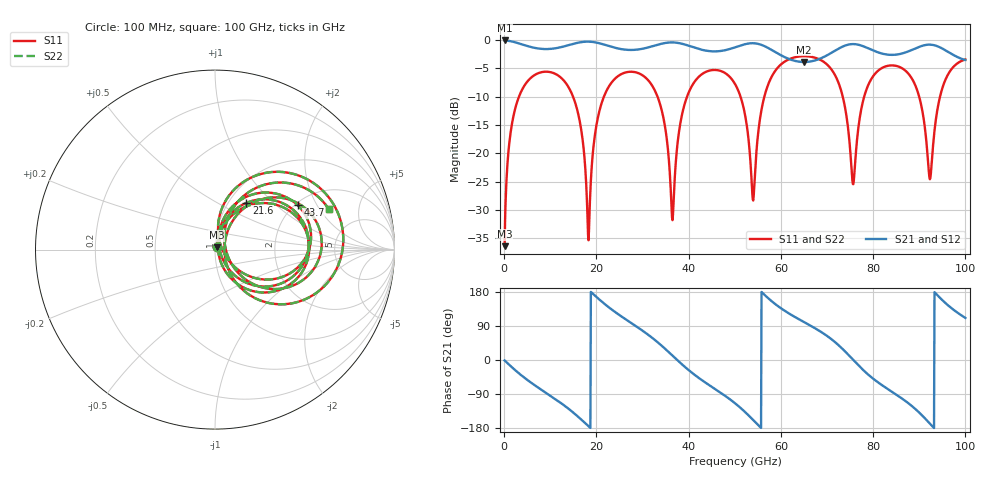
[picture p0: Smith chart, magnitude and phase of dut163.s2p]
! Touchstone file exported from HFSS 2026.1.0
!  File:  C:/ffzhzh/LocalFiles/Ansys_Project_Files/temp_test_TSV_RDL_163_1783465843_7600.aedt
!  Generated:  07:21:00 AM Jul  8, 2026
!  Design:  TSV_RDL
!  Project:  temp_test_TSV_RDL_163_1783465843_7600
! Variables:
!  h_bsmrdl = 4.7um
!  h_ox = 20um
!  h_rdl = 5um
!  h_sub = 58.96um
!  h_tmrdl = 4.99um
!  h_tsv = 58.96um
!  h_via = 3um
!  l_bsmrdl = 376.68um
!  l_sub = 3402.85um
!  l_tmrdl = 429.51um
!  m_sub = 200um
!  pitch = 59.9um
!  r_tsv = 13.04um
!  s_tmrdl = 10um
!  w_bsmrdl = 27.58um
!  w_sub = 500um
!  w_tmrdl = 24.01um
!  x_tsv_center1 = 441.515um
!  x_tsv_center2 = 845.775um
!  x_tsv_center3 = 1299.295um
!  x_tsv_center4 = 1703.555um
!  x_tsv_center5 = 2157.075um
!  x_tsv_center6 = 2561.335um
# GHz S MA R 50.000000
! Terminal data exported
! Port[1] = TM_RDL1_1_T1
! Port[2] = TM_RDL5_1_T1
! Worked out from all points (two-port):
!   1000 points, 100 MHz to 100 GHz, reference 50 ohm
!   highest |S21| = -0.08 dB at 100 MHz (marker M1); lowest = -3.9 dB at 65 GHz (marker M2)
!   |S21| within 3 dB of the highest: start of sweep to 60.96 GHz; 69.09 GHz to 98.45 GHz (29.36 GHz wide, 35 % of centre)
!   lowest |S11| = -36.4 dB at 100 MHz (marker M3), VSWR 1.03, Z = 50.9 + j1.2 ohm
!   |S11| at or under -10 dB: 14.93 GHz to 21.63 GHz (6.703 GHz wide, 36.7 % of centre); 33.25 GHz to 39.66 GHz (6.412 GHz wide, 17.6 % of centre); 51.24 GHz to 56.42 GHz (5.178 GHz wide, 9.62 % of centre) (the widest 3 of 6)
!   |S22| runs from -36.4 to -2.9 dB; largest |S21 - S12| = 4.7e-13
!   S11 on the Smith chart (normalised r, x): 100 MHz: 1.02, +0.02; 21.6 GHz: 1.20, +0.70; 43.7 GHz: 2.06, +1.40; 100 GHz: 2.97, +2.44
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0.1  0.01511 51.0  0.9907 -1.2  0.9907 -1.2  0.01511 51.0
! Gamma 0 0 0 0
! Port Impedance 50 0 50 0
1.7  0.1823 66.5  0.9699 -19.3  0.9699 -19.3  0.1823 66.5
5.2  0.4379 33.5  0.8802 -54.2  0.8802 -54.2  0.4379 33.5
16.8  0.1525 -63.3  0.9585 -158.0  0.9585 -158.0  0.1524 -63.2
18.3  0.01704 12.6  0.9669 -174.7  0.9669 -174.7  0.01727 12.7
21.6  0.3137 56.1  0.9132 149.7  0.9132 149.7  0.3138 56.1
33.4  0.3042 -41.4  0.911 45.6  0.911 45.6  0.3042 -41.5
36.5  0.02564 14.3  0.952 11.5  0.952 11.5  0.0251 14.2
39  0.2599 67.9  0.9163 -16.3  0.9163 -16.3  0.2598 67.9
43.7  0.5224 28.3  0.8063 -60.2  0.8063 -60.2  0.5223 28.3
50.1  0.4057 -22.0  0.8624 -114.6  0.8624 -114.6  0.4055 -22.0
54  0.03824 25.8  0.9365 -158.4  0.9365 -158.4  0.03773 26.1
57.4  0.4199 66.2  0.8434 161.4  0.8434 161.4  0.4199 66.2
65  0.7195 9.9  0.6392 100.3  0.6392 100.3  0.7195 9.9
66.7  0.7088 -0.9  0.6495 88.7  0.6495 88.7  0.7088 -0.9
72.6  0.4074 -46.0  0.8425 38.0  0.8425 38.0  0.4074 -46.1
75.7  0.05327 6.6  0.9207 -0.1  0.9207 -0.1  0.05236 6.7
78.4  0.3507 50.0  0.8626 -32.8  0.8626 -32.8  0.3505 50.1
83.4  0.5938 10.6  0.7409 -78.5  0.7409 -78.5  0.5936 10.7
89.2  0.3923 -34.1  0.8438 -129.9  0.8438 -129.9  0.392 -34.1
92.3  0.05889 9.5  0.9099 -167.8  0.9099 -167.8  0.05904 9.8
100  0.6726 19.5  0.6655 111.0  0.6655 111.0  0.6727 19.5
